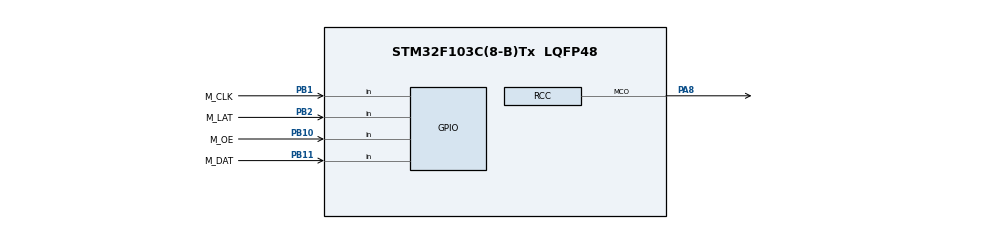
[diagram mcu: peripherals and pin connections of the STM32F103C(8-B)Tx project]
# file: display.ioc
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Mcu.Family=STM32F1
Mcu.Name=STM32F103C(8-B)Tx
Mcu.Package=LQFP48
NVIC.PriorityGroup=NVIC_PRIORITYGROUP_4
PA13.Mode=Serial_Wire
PA13.Signal=SYS_JTMS-SWDIO
PA14.Mode=Serial_Wire
PA14.Signal=SYS_JTCK-SWCLK
PA8.Mode=Clock-out
PA8.Signal=RCC_MCO
PB1.GPIO_Label=M_CLK
PB1.Signal=GPIO_Input
PB10.GPIO_Label=M_OE
PB10.Signal=GPIO_Input
PB11.GPIO_Label=M_DAT
PB11.Signal=GPIO_Input
PB2.GPIO_Label=M_LAT
PB2.Signal=GPIO_Input
ProjectManager.HeapSize=0x200
ProjectManager.StackSize=0x400
ProjectManager.TargetToolchain=STM32CubeIDE
RCC.AHBFreq_Value=8000000
RCC.APB1Freq_Value=8000000
RCC.APB1TimFreq_Value=8000000
RCC.APB2Freq_Value=8000000
RCC.APB2TimFreq_Value=8000000
RCC.HCLKFreq_Value=8000000
RCC.SYSCLKFreq_VALUE=8000000
RCC.SYSCLKSource=RCC_SYSCLKSOURCE_PLLCLK
RCC.USBFreq_Value=8000000
board=custom

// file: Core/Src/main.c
/* USER CODE BEGIN Header */
/**
  ******************************************************************************
  * @file           : main.c
  * @brief          : Main program body
  ******************************************************************************
  * @attention
  *
  * Copyright (c) 2022 STMicroelectronics.
  * All rights reserved.
  *
  * This software is licensed under terms that can be found in the LICENSE file
  * in the root directory of this software component.
  * If no LICENSE file comes with this software, it is provided AS-IS.
  *
  ******************************************************************************
  */
/* USER CODE END Header */
#include "main.h"

void SystemClock_Config(void);
static void MX_GPIO_Init(void);
/* USER CODE BEGIN PFP */

static void clock(void)
{
   CLK_HIGH;
   CLK_LOW;
}

static void latch(void)
{
    LAT_HIGH;
    LAT_LOW;
}

	void mbi1_init(void){

		mbi1=

	}
/* USER CODE END PFP */

int main(void)
{

  /* MCU Configuration--------------------------------------------------------*/

  /* Reset of all peripherals, Initializes the Flash interface and the Systick. */
  HAL_Init();

  /* Configure the system clock */
  SystemClock_Config();

  /* Initialize all configured peripherals */
  MX_GPIO_Init();

  /* Infinite loop */
  while (1)
  {

    /* USER CODE BEGIN 3 */
	  	HAL_GPIO_WritePin(M_DAT_GPIO_Port, M_DAT_Pin,GPIO_PIN_SET);
	  	HAL_GPIO_WritePin(M_OE_GPIO_Port, M_OE_Pin, GPIO_PIN_RESET);
	  	HAL_GPIO_WritePin(M_CLK_GPIO_Port, M_CLK_Pin,GPIO_PIN_SET);
	  	HAL_GPIO_WritePin(M_LAT_GPIO_Port, M_LAT_Pin, GPIO_PIN_SET);

  }
  /* USER CODE END 3 */
}

void SystemClock_Config(void)
{
  RCC_OscInitTypeDef RCC_OscInitStruct = {0};
  RCC_ClkInitTypeDef RCC_ClkInitStruct = {0};

  /** Initializes the RCC Oscillators according to the specified parameters
  * in the RCC_OscInitTypeDef structure.
  */
  RCC_OscInitStruct.OscillatorType = RCC_OSCILLATORTYPE_HSI;
  RCC_OscInitStruct.HSIState = RCC_HSI_ON;
  RCC_OscInitStruct.HSICalibrationValue = RCC_HSICALIBRATION_DEFAULT;
  RCC_OscInitStruct.PLL.PLLState = RCC_PLL_NONE;
  if (HAL_RCC_OscConfig(&RCC_OscInitStruct) != HAL_OK)
  {
    Error_Handler();
  }
  /** Initializes the CPU, AHB and APB buses clocks
  */
  RCC_ClkInitStruct.ClockType = RCC_CLOCKTYPE_HCLK|RCC_CLOCKTYPE_SYSCLK
                              |RCC_CLOCKTYPE_PCLK1|RCC_CLOCKTYPE_PCLK2;
  RCC_ClkInitStruct.SYSCLKSource = RCC_SYSCLKSOURCE_HSI;
  RCC_ClkInitStruct.AHBCLKDivider = RCC_SYSCLK_DIV1;
  RCC_ClkInitStruct.APB1CLKDivider = RCC_HCLK_DIV1;
  RCC_ClkInitStruct.APB2CLKDivider = RCC_HCLK_DIV1;

  if (HAL_RCC_ClockConfig(&RCC_ClkInitStruct, FLASH_LATENCY_0) != HAL_OK)
  {
    Error_Handler();
  }
  HAL_RCC_MCOConfig(RCC_MCO, RCC_MCO1SOURCE_SYSCLK, RCC_MCODIV_1);
}

static void MX_GPIO_Init(void)
{
  GPIO_InitTypeDef GPIO_InitStruct = {0};

  /* GPIO Ports Clock Enable */
  __HAL_RCC_GPIOD_CLK_ENABLE();
  __HAL_RCC_GPIOB_CLK_ENABLE();
  __HAL_RCC_GPIOA_CLK_ENABLE();

  /*Configure GPIO pins : M_CLK_Pin M_LAT_Pin M_OE_Pin M_DAT_Pin */
  GPIO_InitStruct.Pin = M_CLK_Pin|M_LAT_Pin|M_OE_Pin|M_DAT_Pin;
  GPIO_InitStruct.Mode = GPIO_MODE_INPUT;
  GPIO_InitStruct.Pull = GPIO_NOPULL;
  HAL_GPIO_Init(GPIOB, &GPIO_InitStruct);

  /*Configure GPIO pin : PA8 */
  GPIO_InitStruct.Pin = GPIO_PIN_8;
  GPIO_InitStruct.Mode = GPIO_MODE_AF_PP;
  GPIO_InitStruct.Speed = GPIO_SPEED_FREQ_LOW;
  HAL_GPIO_Init(GPIOA, &GPIO_InitStruct);

}

void Error_Handler(void)
{
  __disable_irq();
  while (1)
  {
  }
}
